VERSION 5.7 ;
BUSBITCHARS "[]" ;
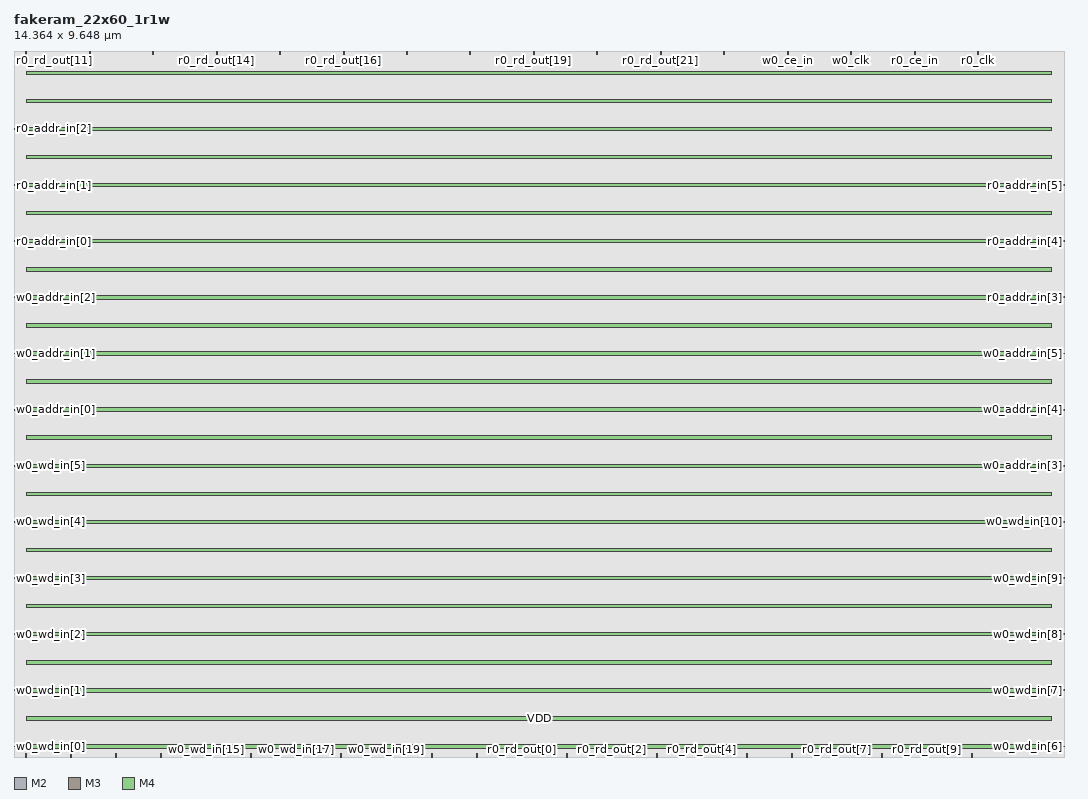
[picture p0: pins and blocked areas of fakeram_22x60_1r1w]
MACRO fakeram_22x60_1r1w
  FOREIGN fakeram_22x60_1r1w 0 0 ;
  SYMMETRY X Y R90 ;
  SIZE 14.364 BY 9.648 ;
  CLASS BLOCK ;
  PIN w0_wd_in[0]
    DIRECTION INPUT ;
    USE SIGNAL ;
    SHAPE ABUTMENT ;
    PORT
      LAYER M2 ;
      RECT 0.000 0.138 0.036 0.150 ;
    END
  END w0_wd_in[0]
  PIN w0_wd_in[1]
    DIRECTION INPUT ;
    USE SIGNAL ;
    SHAPE ABUTMENT ;
    PORT
      LAYER M2 ;
      RECT 0.000 0.906 0.036 0.918 ;
    END
  END w0_wd_in[1]
  PIN w0_wd_in[2]
    DIRECTION INPUT ;
    USE SIGNAL ;
    SHAPE ABUTMENT ;
    PORT
      LAYER M2 ;
      RECT 0.000 1.674 0.036 1.686 ;
    END
  END w0_wd_in[2]
  PIN w0_wd_in[3]
    DIRECTION INPUT ;
    USE SIGNAL ;
    SHAPE ABUTMENT ;
    PORT
      LAYER M2 ;
      RECT 0.000 2.442 0.036 2.454 ;
    END
  END w0_wd_in[3]
  PIN w0_wd_in[4]
    DIRECTION INPUT ;
    USE SIGNAL ;
    SHAPE ABUTMENT ;
    PORT
      LAYER M2 ;
      RECT 0.000 3.210 0.036 3.222 ;
    END
  END w0_wd_in[4]
  PIN w0_wd_in[5]
    DIRECTION INPUT ;
    USE SIGNAL ;
    SHAPE ABUTMENT ;
    PORT
      LAYER M2 ;
      RECT 0.000 3.978 0.036 3.990 ;
    END
  END w0_wd_in[5]
  PIN w0_wd_in[6]
    DIRECTION INPUT ;
    USE SIGNAL ;
    SHAPE ABUTMENT ;
    PORT
      LAYER M2 ;
      RECT 14.328 0.138 14.364 0.150 ;
    END
  END w0_wd_in[6]
  PIN w0_wd_in[7]
    DIRECTION INPUT ;
    USE SIGNAL ;
    SHAPE ABUTMENT ;
    PORT
      LAYER M2 ;
      RECT 14.328 0.906 14.364 0.918 ;
    END
  END w0_wd_in[7]
  PIN w0_wd_in[8]
    DIRECTION INPUT ;
    USE SIGNAL ;
    SHAPE ABUTMENT ;
    PORT
      LAYER M2 ;
      RECT 14.328 1.674 14.364 1.686 ;
    END
  END w0_wd_in[8]
  PIN w0_wd_in[9]
    DIRECTION INPUT ;
    USE SIGNAL ;
    SHAPE ABUTMENT ;
    PORT
      LAYER M2 ;
      RECT 14.328 2.442 14.364 2.454 ;
    END
  END w0_wd_in[9]
  PIN w0_wd_in[10]
    DIRECTION INPUT ;
    USE SIGNAL ;
    SHAPE ABUTMENT ;
    PORT
      LAYER M2 ;
      RECT 14.328 3.210 14.364 3.222 ;
    END
  END w0_wd_in[10]
  PIN w0_wd_in[11]
    DIRECTION INPUT ;
    USE SIGNAL ;
    SHAPE ABUTMENT ;
    PORT
      LAYER M3 ;
      RECT 0.161 0.000 0.175 0.042 ;
    END
  END w0_wd_in[11]
  PIN w0_wd_in[12]
    DIRECTION INPUT ;
    USE SIGNAL ;
    SHAPE ABUTMENT ;
    PORT
      LAYER M3 ;
      RECT 0.777 0.000 0.791 0.042 ;
    END
  END w0_wd_in[12]
  PIN w0_wd_in[13]
    DIRECTION INPUT ;
    USE SIGNAL ;
    SHAPE ABUTMENT ;
    PORT
      LAYER M3 ;
      RECT 1.393 0.000 1.407 0.042 ;
    END
  END w0_wd_in[13]
  PIN w0_wd_in[14]
    DIRECTION INPUT ;
    USE SIGNAL ;
    SHAPE ABUTMENT ;
    PORT
      LAYER M3 ;
      RECT 2.009 0.000 2.023 0.042 ;
    END
  END w0_wd_in[14]
  PIN w0_wd_in[15]
    DIRECTION INPUT ;
    USE SIGNAL ;
    SHAPE ABUTMENT ;
    PORT
      LAYER M3 ;
      RECT 2.625 0.000 2.639 0.042 ;
    END
  END w0_wd_in[15]
  PIN w0_wd_in[16]
    DIRECTION INPUT ;
    USE SIGNAL ;
    SHAPE ABUTMENT ;
    PORT
      LAYER M3 ;
      RECT 3.241 0.000 3.255 0.042 ;
    END
  END w0_wd_in[16]
  PIN w0_wd_in[17]
    DIRECTION INPUT ;
    USE SIGNAL ;
    SHAPE ABUTMENT ;
    PORT
      LAYER M3 ;
      RECT 3.857 0.000 3.871 0.042 ;
    END
  END w0_wd_in[17]
  PIN w0_wd_in[18]
    DIRECTION INPUT ;
    USE SIGNAL ;
    SHAPE ABUTMENT ;
    PORT
      LAYER M3 ;
      RECT 4.473 0.000 4.487 0.042 ;
    END
  END w0_wd_in[18]
  PIN w0_wd_in[19]
    DIRECTION INPUT ;
    USE SIGNAL ;
    SHAPE ABUTMENT ;
    PORT
      LAYER M3 ;
      RECT 5.089 0.000 5.103 0.042 ;
    END
  END w0_wd_in[19]
  PIN w0_wd_in[20]
    DIRECTION INPUT ;
    USE SIGNAL ;
    SHAPE ABUTMENT ;
    PORT
      LAYER M3 ;
      RECT 5.705 0.000 5.719 0.042 ;
    END
  END w0_wd_in[20]
  PIN w0_wd_in[21]
    DIRECTION INPUT ;
    USE SIGNAL ;
    SHAPE ABUTMENT ;
    PORT
      LAYER M3 ;
      RECT 6.321 0.000 6.335 0.042 ;
    END
  END w0_wd_in[21]
  PIN r0_rd_out[0]
    DIRECTION OUTPUT ;
    USE SIGNAL ;
    SHAPE ABUTMENT ;
    PORT
      LAYER M3 ;
      RECT 6.937 0.000 6.951 0.042 ;
    END
  END r0_rd_out[0]
  PIN r0_rd_out[1]
    DIRECTION OUTPUT ;
    USE SIGNAL ;
    SHAPE ABUTMENT ;
    PORT
      LAYER M3 ;
      RECT 7.553 0.000 7.567 0.042 ;
    END
  END r0_rd_out[1]
  PIN r0_rd_out[2]
    DIRECTION OUTPUT ;
    USE SIGNAL ;
    SHAPE ABUTMENT ;
    PORT
      LAYER M3 ;
      RECT 8.169 0.000 8.183 0.042 ;
    END
  END r0_rd_out[2]
  PIN r0_rd_out[3]
    DIRECTION OUTPUT ;
    USE SIGNAL ;
    SHAPE ABUTMENT ;
    PORT
      LAYER M3 ;
      RECT 8.785 0.000 8.799 0.042 ;
    END
  END r0_rd_out[3]
  PIN r0_rd_out[4]
    DIRECTION OUTPUT ;
    USE SIGNAL ;
    SHAPE ABUTMENT ;
    PORT
      LAYER M3 ;
      RECT 9.401 0.000 9.415 0.042 ;
    END
  END r0_rd_out[4]
  PIN r0_rd_out[5]
    DIRECTION OUTPUT ;
    USE SIGNAL ;
    SHAPE ABUTMENT ;
    PORT
      LAYER M3 ;
      RECT 10.017 0.000 10.031 0.042 ;
    END
  END r0_rd_out[5]
  PIN r0_rd_out[6]
    DIRECTION OUTPUT ;
    USE SIGNAL ;
    SHAPE ABUTMENT ;
    PORT
      LAYER M3 ;
      RECT 10.633 0.000 10.647 0.042 ;
    END
  END r0_rd_out[6]
  PIN r0_rd_out[7]
    DIRECTION OUTPUT ;
    USE SIGNAL ;
    SHAPE ABUTMENT ;
    PORT
      LAYER M3 ;
      RECT 11.249 0.000 11.263 0.042 ;
    END
  END r0_rd_out[7]
  PIN r0_rd_out[8]
    DIRECTION OUTPUT ;
    USE SIGNAL ;
    SHAPE ABUTMENT ;
    PORT
      LAYER M3 ;
      RECT 11.865 0.000 11.879 0.042 ;
    END
  END r0_rd_out[8]
  PIN r0_rd_out[9]
    DIRECTION OUTPUT ;
    USE SIGNAL ;
    SHAPE ABUTMENT ;
    PORT
      LAYER M3 ;
      RECT 12.481 0.000 12.495 0.042 ;
    END
  END r0_rd_out[9]
  PIN r0_rd_out[10]
    DIRECTION OUTPUT ;
    USE SIGNAL ;
    SHAPE ABUTMENT ;
    PORT
      LAYER M3 ;
      RECT 13.097 0.000 13.111 0.042 ;
    END
  END r0_rd_out[10]
  PIN r0_rd_out[11]
    DIRECTION OUTPUT ;
    USE SIGNAL ;
    SHAPE ABUTMENT ;
    PORT
      LAYER M3 ;
      RECT 0.161 9.606 0.175 9.648 ;
    END
  END r0_rd_out[11]
  PIN r0_rd_out[12]
    DIRECTION OUTPUT ;
    USE SIGNAL ;
    SHAPE ABUTMENT ;
    PORT
      LAYER M3 ;
      RECT 1.029 9.606 1.043 9.648 ;
    END
  END r0_rd_out[12]
  PIN r0_rd_out[13]
    DIRECTION OUTPUT ;
    USE SIGNAL ;
    SHAPE ABUTMENT ;
    PORT
      LAYER M3 ;
      RECT 1.897 9.606 1.911 9.648 ;
    END
  END r0_rd_out[13]
  PIN r0_rd_out[14]
    DIRECTION OUTPUT ;
    USE SIGNAL ;
    SHAPE ABUTMENT ;
    PORT
      LAYER M3 ;
      RECT 2.765 9.606 2.779 9.648 ;
    END
  END r0_rd_out[14]
  PIN r0_rd_out[15]
    DIRECTION OUTPUT ;
    USE SIGNAL ;
    SHAPE ABUTMENT ;
    PORT
      LAYER M3 ;
      RECT 3.633 9.606 3.647 9.648 ;
    END
  END r0_rd_out[15]
  PIN r0_rd_out[16]
    DIRECTION OUTPUT ;
    USE SIGNAL ;
    SHAPE ABUTMENT ;
    PORT
      LAYER M3 ;
      RECT 4.501 9.606 4.515 9.648 ;
    END
  END r0_rd_out[16]
  PIN r0_rd_out[17]
    DIRECTION OUTPUT ;
    USE SIGNAL ;
    SHAPE ABUTMENT ;
    PORT
      LAYER M3 ;
      RECT 5.369 9.606 5.383 9.648 ;
    END
  END r0_rd_out[17]
  PIN r0_rd_out[18]
    DIRECTION OUTPUT ;
    USE SIGNAL ;
    SHAPE ABUTMENT ;
    PORT
      LAYER M3 ;
      RECT 6.237 9.606 6.251 9.648 ;
    END
  END r0_rd_out[18]
  PIN r0_rd_out[19]
    DIRECTION OUTPUT ;
    USE SIGNAL ;
    SHAPE ABUTMENT ;
    PORT
      LAYER M3 ;
      RECT 7.105 9.606 7.119 9.648 ;
    END
  END r0_rd_out[19]
  PIN r0_rd_out[20]
    DIRECTION OUTPUT ;
    USE SIGNAL ;
    SHAPE ABUTMENT ;
    PORT
      LAYER M3 ;
      RECT 7.973 9.606 7.987 9.648 ;
    END
  END r0_rd_out[20]
  PIN r0_rd_out[21]
    DIRECTION OUTPUT ;
    USE SIGNAL ;
    SHAPE ABUTMENT ;
    PORT
      LAYER M3 ;
      RECT 8.841 9.606 8.855 9.648 ;
    END
  END r0_rd_out[21]
  PIN w0_addr_in[0]
    DIRECTION INPUT ;
    USE SIGNAL ;
    SHAPE ABUTMENT ;
    PORT
      LAYER M2 ;
      RECT 0.000 4.746 0.036 4.758 ;
    END
  END w0_addr_in[0]
  PIN w0_addr_in[1]
    DIRECTION INPUT ;
    USE SIGNAL ;
    SHAPE ABUTMENT ;
    PORT
      LAYER M2 ;
      RECT 0.000 5.514 0.036 5.526 ;
    END
  END w0_addr_in[1]
  PIN w0_addr_in[2]
    DIRECTION INPUT ;
    USE SIGNAL ;
    SHAPE ABUTMENT ;
    PORT
      LAYER M2 ;
      RECT 0.000 6.282 0.036 6.294 ;
    END
  END w0_addr_in[2]
  PIN w0_addr_in[3]
    DIRECTION INPUT ;
    USE SIGNAL ;
    SHAPE ABUTMENT ;
    PORT
      LAYER M2 ;
      RECT 14.328 3.978 14.364 3.990 ;
    END
  END w0_addr_in[3]
  PIN w0_addr_in[4]
    DIRECTION INPUT ;
    USE SIGNAL ;
    SHAPE ABUTMENT ;
    PORT
      LAYER M2 ;
      RECT 14.328 4.746 14.364 4.758 ;
    END
  END w0_addr_in[4]
  PIN w0_addr_in[5]
    DIRECTION INPUT ;
    USE SIGNAL ;
    SHAPE ABUTMENT ;
    PORT
      LAYER M2 ;
      RECT 14.328 5.514 14.364 5.526 ;
    END
  END w0_addr_in[5]
  PIN r0_addr_in[0]
    DIRECTION INPUT ;
    USE SIGNAL ;
    SHAPE ABUTMENT ;
    PORT
      LAYER M2 ;
      RECT 0.000 7.050 0.036 7.062 ;
    END
  END r0_addr_in[0]
  PIN r0_addr_in[1]
    DIRECTION INPUT ;
    USE SIGNAL ;
    SHAPE ABUTMENT ;
    PORT
      LAYER M2 ;
      RECT 0.000 7.818 0.036 7.830 ;
    END
  END r0_addr_in[1]
  PIN r0_addr_in[2]
    DIRECTION INPUT ;
    USE SIGNAL ;
    SHAPE ABUTMENT ;
    PORT
      LAYER M2 ;
      RECT 0.000 8.586 0.036 8.598 ;
    END
  END r0_addr_in[2]
  PIN r0_addr_in[3]
    DIRECTION INPUT ;
    USE SIGNAL ;
    SHAPE ABUTMENT ;
    PORT
      LAYER M2 ;
      RECT 14.328 6.282 14.364 6.294 ;
    END
  END r0_addr_in[3]
  PIN r0_addr_in[4]
    DIRECTION INPUT ;
    USE SIGNAL ;
    SHAPE ABUTMENT ;
    PORT
      LAYER M2 ;
      RECT 14.328 7.050 14.364 7.062 ;
    END
  END r0_addr_in[4]
  PIN r0_addr_in[5]
    DIRECTION INPUT ;
    USE SIGNAL ;
    SHAPE ABUTMENT ;
    PORT
      LAYER M2 ;
      RECT 14.328 7.818 14.364 7.830 ;
    END
  END r0_addr_in[5]
  PIN w0_we_in
    DIRECTION INPUT ;
    USE SIGNAL ;
    SHAPE ABUTMENT ;
    PORT
      LAYER M3 ;
      RECT 9.709 9.606 9.723 9.648 ;
    END
  END w0_we_in
  PIN w0_ce_in
    DIRECTION INPUT ;
    USE SIGNAL ;
    SHAPE ABUTMENT ;
    PORT
      LAYER M3 ;
      RECT 10.577 9.606 10.591 9.648 ;
    END
  END w0_ce_in
  PIN w0_clk
    DIRECTION INPUT ;
    USE SIGNAL ;
    SHAPE ABUTMENT ;
    PORT
      LAYER M3 ;
      RECT 11.445 9.606 11.459 9.648 ;
    END
  END w0_clk
  PIN r0_ce_in
    DIRECTION INPUT ;
    USE SIGNAL ;
    SHAPE ABUTMENT ;
    PORT
      LAYER M3 ;
      RECT 12.313 9.606 12.327 9.648 ;
    END
  END r0_ce_in
  PIN r0_clk
    DIRECTION INPUT ;
    USE SIGNAL ;
    SHAPE ABUTMENT ;
    PORT
      LAYER M3 ;
      RECT 13.181 9.606 13.195 9.648 ;
    END
  END r0_clk
  PIN VSS
    DIRECTION INOUT ;
    USE GROUND ;
    PORT
      LAYER M4 ;
      RECT 0.168 0.120 14.196 0.168 ;
      RECT 0.168 0.504 14.196 0.552 ;
      RECT 0.168 0.888 14.196 0.936 ;
      RECT 0.168 1.272 14.196 1.320 ;
      RECT 0.168 1.656 14.196 1.704 ;
      RECT 0.168 2.040 14.196 2.088 ;
      RECT 0.168 2.424 14.196 2.472 ;
      RECT 0.168 2.808 14.196 2.856 ;
      RECT 0.168 3.192 14.196 3.240 ;
      RECT 0.168 3.576 14.196 3.624 ;
      RECT 0.168 3.960 14.196 4.008 ;
      RECT 0.168 4.344 14.196 4.392 ;
      RECT 0.168 4.728 14.196 4.776 ;
      RECT 0.168 5.112 14.196 5.160 ;
      RECT 0.168 5.496 14.196 5.544 ;
      RECT 0.168 5.880 14.196 5.928 ;
      RECT 0.168 6.264 14.196 6.312 ;
      RECT 0.168 6.648 14.196 6.696 ;
      RECT 0.168 7.032 14.196 7.080 ;
      RECT 0.168 7.416 14.196 7.464 ;
      RECT 0.168 7.800 14.196 7.848 ;
      RECT 0.168 8.184 14.196 8.232 ;
      RECT 0.168 8.568 14.196 8.616 ;
      RECT 0.168 8.952 14.196 9.000 ;
      RECT 0.168 9.336 14.196 9.384 ;
    END
  END VSS
  PIN VDD
    DIRECTION INOUT ;
    USE POWER ;
    PORT
      LAYER M4 ;
      RECT 0.168 0.120 14.196 0.168 ;
      RECT 0.168 0.504 14.196 0.552 ;
      RECT 0.168 0.888 14.196 0.936 ;
      RECT 0.168 1.272 14.196 1.320 ;
      RECT 0.168 1.656 14.196 1.704 ;
      RECT 0.168 2.040 14.196 2.088 ;
      RECT 0.168 2.424 14.196 2.472 ;
      RECT 0.168 2.808 14.196 2.856 ;
      RECT 0.168 3.192 14.196 3.240 ;
      RECT 0.168 3.576 14.196 3.624 ;
      RECT 0.168 3.960 14.196 4.008 ;
      RECT 0.168 4.344 14.196 4.392 ;
      RECT 0.168 4.728 14.196 4.776 ;
      RECT 0.168 5.112 14.196 5.160 ;
      RECT 0.168 5.496 14.196 5.544 ;
      RECT 0.168 5.880 14.196 5.928 ;
      RECT 0.168 6.264 14.196 6.312 ;
      RECT 0.168 6.648 14.196 6.696 ;
      RECT 0.168 7.032 14.196 7.080 ;
      RECT 0.168 7.416 14.196 7.464 ;
      RECT 0.168 7.800 14.196 7.848 ;
      RECT 0.168 8.184 14.196 8.232 ;
      RECT 0.168 8.568 14.196 8.616 ;
      RECT 0.168 8.952 14.196 9.000 ;
      RECT 0.168 9.336 14.196 9.384 ;
    END
  END VDD
  OBS
    LAYER M1 ;
    RECT 0 0 14.364 9.648 ;
    LAYER M2 ;
    RECT 0 0 14.364 9.648 ;
    LAYER M3 ;
    RECT 0 0 14.364 9.648 ;
    LAYER M4 ;
    RECT 0 0 14.364 9.648 ;
  END
END fakeram_22x60_1r1w

END LIBRARY
